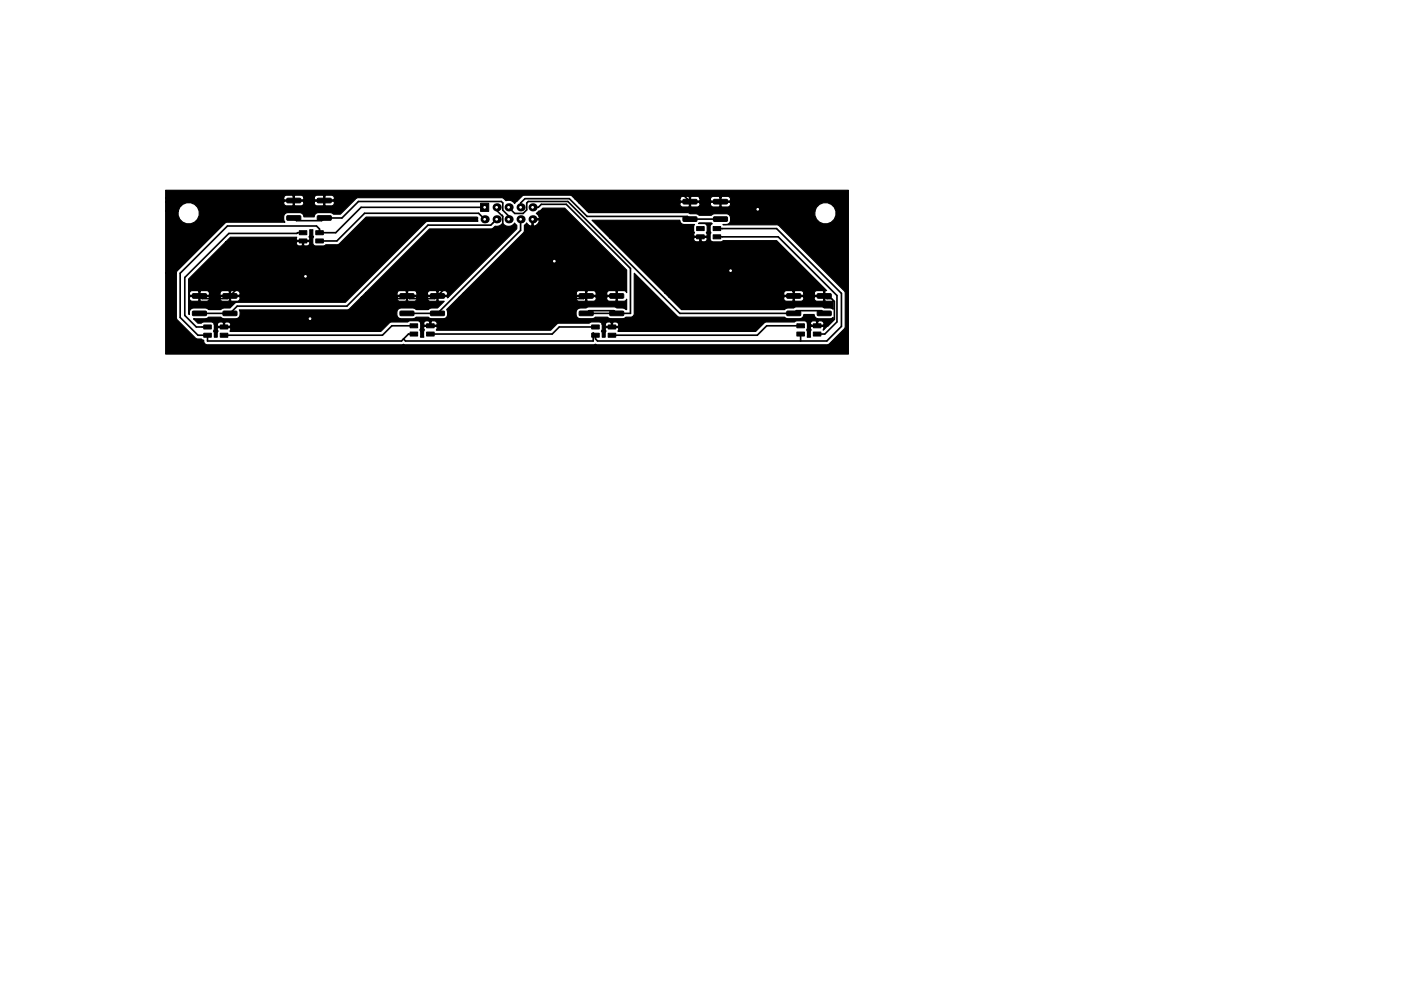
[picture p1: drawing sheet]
<svg xmlns="http://www.w3.org/2000/svg" width="297mm" height="210mm" viewBox="0 0 297 210" stroke-linecap="round" stroke-linejoin="round" font-family="sans-serif">
<g fill="#000" stroke="#000" stroke-width=".21">
<path d="M63.4 50.7h1.6v.8h-1.6zM63.4 48.9h1.6v.9h-1.6zM60.9 42.1h2.7l.2 .1v.7l-.2 .1h-2.6l-.2-.2zM60.9 45.8h2.7l.2 .1v.7l-.2 .1h-2.6l-.2-.2zM67 50.7h1.6v.8h-1.6zM67 48.9h1.6v.9h-1.6zM67.3 42.1h2.8l.2 .1v.6l-.3 .2h-2.6l-.1-.2zM67.3 45.8h2.8l.2 .1v.6l-.3 .2h-2.5l-.2-.2zM101.9 43.1h1.7v1.8h-1.7zM144.9 46.1l2.7-.1 .2 .2v.6l-.2 .2h-2.6l-.2-.2zM144.9 42.4l2.7-.1 .2 .2v.6l-.2 .2h-2.6l-.2-.2zM147.7 48.1h1.6v.8h-1.6z"/>
<path d="M147.7 49.8h1.6v.9h-1.6zM151.2 48.1h1.6v.8h-1.6zM151.2 49.8h1.6v.9h-1.6zM151.3 46.1l2.8-.1 .2 .2-.1 .6-.2 .2h-2.5l-.2-.2zM151.3 42.4l2.8-.1 .2 .2-.1 .6-.2 .2h-2.5l-.2-.2zM40.9 62.4l2.7-.1 .2 .2v.6l-.2 .2h-2.6l-.2-.2zM40.9 66.1l2.7-.1 .2 .2v.6l-.2 .2h-2.6l-.2-.2zM43.2 70.7h1.6v.8h-1.6zM43.2 68.9h1.6v.9h-1.6zM46.7 70.7h1.6v.8h-1.6zM46.7 68.9h1.6v.9h-1.6zM47.3 62.4l2.8-.1 .2 .2-.1 .6-.2 .2h-2.6l-.1-.2z"/>
<path d="M47.3 66.1l2.8-.1 .2 .2-.1 .6-.2 .2h-2.6l-.1-.2zM84.9 62.4l2.7-.1 .2 .2v.6l-.2 .2h-2.6l-.2-.2zM84.9 66.1l2.7-.1 .2 .2v.6l-.2 .2h-2.6l-.2-.2zM87 68.7h1.5v.8h-1.5zM87 70.4h1.5v.9h-1.5zM90.4 68.7h1.7v.8h-1.7zM90.4 70.4h1.7v.9h-1.7zM91.3 62.4l2.8-.1 .2 .2v.6l-.3 .2h-2.6l-.1-.2zM91.3 66.1l2.8-.1 .2 .2v.6l-.3 .2h-2.6l-.1-.2zM122.9 66.1l2.7-.1 .2 .2v.6l-.2 .2h-2.6l-.2-.2zM122.9 62.4l2.7-.1 .2 .2v.6l-.2 .2h-2.6l-.2-.2zM125.5 70.7h1.6v.8h-1.6z"/>
<path d="M125.5 68.9h1.6v.9h-1.6zM128.9 70.7h1.6v.8h-1.6zM128.9 68.9h1.6v.9h-1.6zM129.3 66.1l2.8-.1 .2 .2-.1 .6-.2 .2h-2.6l-.1-.2zM129.3 62.4l2.8-.1 .2 .2-.1 .6-.2 .2h-2.6l-.1-.2zM166.9 66.1l2.7-.1 .2 .2v.6l-.2 .2h-2.6l-.2-.2zM166.9 62.4l2.7-.1 .2 .2v.6l-.2 .2h-2.6l-.2-.2zM168.9 68.7h1.7v.8h-1.7zM168.9 70.4h1.7v.9h-1.7zM172.5 68.7h1.5v.8h-1.5zM172.5 70.4h1.5v.9h-1.5zM173.3 66.1l2.8-.1 .2 .2-.1 .6-.2 .2h-2.6l-.1-.2z"/>
<path d="M173.3 62.4l2.8-.1 .2 .2-.1 .6-.2 .2h-2.6l-.1-.2z"/>
<circle cx="64.8" cy="58.6" r=".6"/>
<circle cx="117.5" cy="55.4" r=".6"/>
<circle cx="154.9" cy="57.4" r=".6"/>
<circle cx="160.7" cy="44.4" r=".6"/>
<circle cx="65.7" cy="67.6" r=".6"/>
</g>
<g fill="#000">
<circle cx="102.8" cy="46.5" r=".86"/>
<circle cx="105.3" cy="44" r=".86"/>
<circle cx="105.3" cy="46.5" r=".86"/>
<circle cx="107.8" cy="44" r=".86"/>
<circle cx="107.8" cy="46.5" r=".86"/>
<circle cx="110.4" cy="46.5" r=".86"/>
<circle cx="110.4" cy="44" r=".86"/>
<circle cx="112.9" cy="46.5" r=".86"/>
<circle cx="112.9" cy="44" r=".86"/>
</g>
<g fill="none" stroke="#000" stroke-width=".35">
<path d="M62.3 46.2l.6 .6h5.3l.6-.6h3.7l3.5-3.5h30.3l.3 .3v1.6l1.3 1.3-.1 .6M62.3 42.5h8.4l1.2-1.1h73l1.4 1.4h12.7l1.7 1.6M64.3 51.1h-3.9l-12.2 12.3h-5.3l-.6-.6M64.3 49.4h-1.2l-.2 .1h-14.4l-9.3 9.4v8l2.4 2.5h2.4M64.8 58.6l-4.2 4.2h-11.8M102.8 46.5l-1.3-1.3h-24.2l-5.9 5.9h-3.7M102.8 44h-26.2l-5.4 5.4h-3.5v-.8l-.6-.7h-18.9l-10 10.1v9.3l3.8 3.8h2v1.2h41.1l1.5-1.4h1.1M105.3 44v.6l1.3 1.3v3l-14.4 14.5h-5.3l-.6-.6-.6 .6h-3.5l-1.7 1.6v2.9M105.3 46.5l-1.2 1.3h-13.4l-17.1 17.1h-23.3l-1.5 1.6h-6.5M107.8 44l1.3 1.3h1.8l.8-.8v-1.4l.3-.4h8.4l23.7 23.8h24.2l.6-.6h5.3l.6 .6M110.4 46.5v2.4l-17.6 17.6h-6.5M110.4 44v-.9l.9-1h9.4l3.8 3.8h21.2l.6 .6h6.5"/>
<path d="M112.9 44h1.2l.7-.7h5.3l13.6 13.7v9.5h-9.4l.6-.6h5.3l.6 .6M112.9 46.5v10.9l6 6M117.5 55.4l-4.6 .1M148.5 50.2v.8l11.8 11.8h14.5l.5 .6h1l.6 .5v3.8l-1.4 1.4h-3.4l-1.4-1.4h-52.4l-.4-.3-.3 .3h-26.7l-.1 .2M152 50.2h13l12.4 12.5v5.6l-2.5 2.6h-1.6M152 48.5h12.6l13.8 13.7v7l-3.1 3.1h-48.6l-.5-.4v-.8l-.4-.5v1.7h-39.8l-.5-.4M65.7 67.6h2.3l.3 .3M87.7 69.1h-4.6l-2 2h-33.6M90.8 67.9h-40.7l-1.5 1.5h-1.1M90.8 67.9l.5 .4v.8M118.9 63.4l-1 .9v3.2M126.2 69.4h-7.6l-1.5 1.5h-25.8"/>
<path d="M129.6 67.7l.2 1.7M130.8 62.8h-6.5l-.6 .6h-4.8M169.7 69.1h-7.1l-2 2h-30.8M169.7 70.9v1.4"/>
</g>
<path d="M48.9 50.3h14l-.1 .5 .2 .2h2.5a.48 .48 0 0 0 0-.7 1.81 1.81 0 0 0 .2-1.5h.6a1.81 1.81 0 0 0 .2 1.4 1.73 1.73 0 0 0 0 1.8l.5 .2h1.6l.5-.3h2.6l5.9-5.8h23.5l.2 .1v.8h-10.9l-17.2 17.1h-22.9l-.6 .3-.9 .9h-1.3l-.7 .4h-2.6l-.7-.4h-2.5a1.06 1.06 0 0 0-.9 1.4l-.1-.1v-3.5h.2a.68 .68 0 0 0 .5 .8h1.3l.2-.1v-.9h.2v.9l.2 .1h1.3a.68 .68 0 0 0 .5-.8h2.2a.68 .68 0 0 0 .5 .8h1.4l.1-.1v-.9h.3v.9l.1 .1h1.4a.61 .61 0 0 0 .3-1h-3.9l-.2 .2-6.3-.2-.3 .2v-.9h.2l.1 .5h1.9v-.9h.2v.9h1.9l.1-.5h2.2l.2 .5h1.8v-.9h.3v.9h1.8a.6 .6 0 0 0-.3-1h-1.4l-.1 .1-.4-.1h-1.4l-.5 .5h-2.2l-.5-.5h-1.3l-.2 .1-.4-.1h-1.3l-.7 .5v-3l7.8-7.8h15a.65 .65 0 0 0 .5 .8h.7l.1-.2v-.7h.3v.7l.1 .2h.7a.57 .57 0 0 0 .3-.9h-2.5l-.2 .1h-15zM105.2 43.8l.2 .1v.2h-.3zM106.5 45.6l.1 .1zM41 67.6h2.5l.7-.3h2.6l.7 .3h2.5a1.16 1.16 0 0 0 .7-1.8h22.9l.5-.3 2.5-2.4h7.5a.68 .68 0 0 0 .6 .8h1.3l.2-.1v-.9h.2v.9l.2 .1 1.5-.1 .3-.4v-.3h2.2a.68 .68 0 0 0 .5 .8h1.4l.1-.1v-.9h-1.8l-.2 .2h-2.2l-.1-.2-11.7 .2 .9-.9h6.6l.2 .5h1.9v-.9h.2v.9h1.9l.1-.5h2.2l.2 .5h1.8v-.9h.3v.9h1.8l.2-.2a.68 .68 0 0 0-.5-.8h-1.4l-.1 .1-.4-.1h-1.4l-.5 .5h-2.2l-.5-.5h-1.3l-.2 .1-.4-.1h-1.3l-.6 .5h-6.6l13.6-13.6h13l.3-.1 .6-.5h.1a1.37 1.37 0 0 0 1.5-.7 1.49 1.49 0 0 0 2.5 0l.5 .5v.7l-14.7 14.7-.2-.3h-1.8v.9l.1 .1h1.2l-1.4 1.4h-1.3l-.7 .4h-2.6l-.7-.4h-2.5a1.17 1.17 0 0 0-.9 1.2 1.17 1.17 0 0 0 .9 1.1h2.5l.7-.3h2.6l.7 .3h2.8a1.35 1.35 0 0 0 .4-1.9l2.6-2.6h24.9a.68 .68 0 0 0 .5 .8h1.3l.2-.1v-.9h.2v.9l.2 .1 1.5-.1 .3-.4v-.3h2.2a.68 .68 0 0 0 .5 .8h1.4l.1-.1v-.9h-1.8l-.2 .2h-2.2l-.1-.2h-4l-.1 .2h-24.9l.9-.9h24l.1 .5h1.9v-.9h.2v.9h1.9l.1-.5h2.2l.2 .5h1.8v-.9l-.1-.1h-1.4l-.5 .5h-2.2l-.5-.5h-1.3l-.2 .1-.4-.1h-1.3l-.5 .5h-24l12.8-12.7 .2-.6v-1.1l.5-.5 .4 .5 .5 .2 .2-.1v-1.2h.2v1.2a1.09 1.09 0 0 0 1.4-1l-.1-.2h-1.5v-.3h1.5l.1-.2-.3-.6-.4-.3 1.4-1.1h4.6l13.2 13.1v4.8l-.5-.4h-1.4l-.1 .1v2l.1 .1h1.4l.5-.4v2.2l-.6-.3-1.5-.1-.6-.2h-5.3l-.6 .2h-1.3a1.17 1.17 0 0 0-.9 1.2 1.17 1.17 0 0 0 .9 1.1h2.5l.7-.3h2.6l.7 .3h2.5l.7-.3h1.3a.79 .79 0 0 0 .5-.9v-8.4l9.3 9.3h22.6l.6 .3h2.5a.9 .9 0 0 0 .9-.9h2.2a.9 .9 0 0 0 .9 .9h2.5l.6-.2v.6l-2.1 2a.48 .48 0 0 0 0-.7h-2.5l-.2 .4 .2 .3a1.84 1.84 0 0 0-.1 1.5h-.8l.1-1.1-.2-.4 .2-.5v-.9h.6l.2 .4h1.1v-.8h.3v.8h1.1l.2-.2a.65 .65 0 0 0-.5-.7h-.7l-.1 .1-1.1-.1-.5 .5h-.6l-.2-.4-.4-.1h-1.7l-.5 .2h-5.8l-.6 .2-1.8 1.8h-29.1l.1-.6-.2-.2h-2.5a.48 .48 0 0 0 0 .7l-.2 .5v.8h-.6v-.8a.64 .64 0 0 1 0-.9v-1h.6l.2 .4h1.1v-.7h.3v.7h1.1a.55 .55 0 0 0 .2-.5 .55 .55 0 0 0-.5-.4h-.7l-.1 .2-1.1-.2-.5 .5h-.6l-.2-.3-.4-.2h-1.6l-.6 .3-6.3-.1-.6 .3-1.3 1.3h-24.1l.1-.7-.2-.1h-2.5a.48 .48 0 0 0 0 .7l-.2 .4 .1 1.1h-.8a1.84 1.84 0 0 0-.1-1.5l.2-.5v-.9h.6l.2 .4h1.1v-.8h.3v.8h1.1a.55 .55 0 0 0 .2-.6 .55 .55 0 0 0-.5-.3h-.7l-.1 .1-1.1-.1-.5 .5h-.6l-.2-.4-.5-.1h-1.5l-.6 .2h-3.3l-.6 .2-1.8 1.8h-31.9l.1-.6-.1-.2h-2.6a.48 .48 0 0 0 0 .7l-.1 .5v.8h-.7v-.8a.64 .64 0 0 1 0-.9v-1h.7l.1 .4h1.2v-.7h.2v.7h1.2a.55 .55 0 0 0 .1-.5 .55 .55 0 0 0-.5-.4h-.6l-.2 .2-1-.2-.5 .5h-.7l-.1-.3-.5-.2h-1.6l-.5 .3h-.7zM125.5 46.7h18.6a.9 .9 0 0 0 .9 .9h2.2a1.74 1.74 0 0 0 0 1.8 .48 .48 0 0 0 0 .7h2.6a.48 .48 0 0 0 0-.7 1.73 1.73 0 0 0 0-1.8l-.5-.2h-1.2l.1-.1h2.6l.2 .2-.3 .1a1.73 1.73 0 0 0 0 1.8 1.73 1.73 0 0 0 0 1.7l.5 .2h1.6l.5-.2h11.4l10.6 10.6-.4 .1v2l.1 .1 1.6-.1v1.8l-.3-.2-1.5-.1-.6-.2h-5.3l-.6 .2-1.6 .1-.3 .3h-21.9l-2.6-2.6h24.3a.68 .68 0 0 0 .5 .8h1.3l.2-.1v-.9h.2v.9l.2 .1h1.3a.68 .68 0 0 0 .5-.8h2.2a.68 .68 0 0 0 .5 .8h1.4l.1-.1v-.9h-1.8l-.2 .2h-2.2l-.1-.2h-4l-.1 .2h-24.3l-.9-.9h25.2l.1 .5h1.9v-.9h.2v.9h1.9l.1-.5h2.2l.2 .5h1.8v-.9l-.1-.1h-1.4l-.5 .5h-2.2l-.5-.5h-1.3l-.2 .1-.4-.1h-1.3l-.5 .5h-25.2l-11.7-11.7h17.8a.65 .65 0 0 0 .5 .8h.6l.2-.2v-.7h.2v.7l.2 .2h.6a.57 .57 0 0 0 .4-.9h-2.6l-.1 .1h-17.8zM35.1 40.4h144.8v34.7h-144.8v-17.1h2.3v9.7l4 4 .6 .2h.7l.5 .3a.81 .81 0 0 0 .9 1h41l.4-.2 .5 .2h39.8l.4-.2 .5 .2h48.6l.6-.3 3.3-3.3v-7.4l-.2-.5-14-14-11.7-.1h.7a1.17 1.17 0 0 0 .9-1.1 1.17 1.17 0 0 0-.9-1.2h-2.5l-.7 .4h-2.6l-.3-.3-1.6-.1-.6-.2h-20.9l-.3-.3h48.3a2.28 2.28 0 0 0 2.6 2.7 2.28 2.28 0 0 0 1.5-3.5 2.28 2.28 0 0 0-3.8 0l-.3 .8h-48.3l-1.7-1.7h21.4a.68 .68 0 0 0 .5 .8h1.3l.2-.1v-.9h.2v.9l.2 .1h1.3a.68 .68 0 0 0 .5-.8h2.2a.68 .68 0 0 0 .5 .8h1.4l.1-.1v-.9h.3v.9l.1 .1h1.4a.61 .61 0 0 0 .3-1h-3.9l-.2 .2h-2.2l-.1-.2h-4l-.1 .2h-21.4l-.9-.9h22.3l.1 .5h1.9v-.9h.2v.9h1.9l.1-.5h2.2l.2 .5h1.8v-.9h.3v.9h1.8a.6 .6 0 0 0-.3-1h-1.4l-.1 .1-.4-.1h-1.4l-.5 .5h-2.2l-.5-.5h-1.3l-.2 .1-.4-.1h-1.3l-.5 .5h-22.3l-.6-.6-.6-.3h-9.4l-.6 .3-1.6 1.6a1.46 1.46 0 0 0-1.8-.6l-.4-.4-.6-.3h-30.3l-.6 .3-3.2 3.2h-1.5l-.7-.3h-2.5a.9 .9 0 0 0-.9 .9h-2.2a.9 .9 0 0 0-.9-.9h-2.5a1.25 1.25 0 0 0-.6 2l-12.5 .1-10.3 10.2-.2 .6h-2.3v-13.2h2.7a2.28 2.28 0 0 0 2.6 2.7 2.28 2.28 0 0 0 1.5-3.5 2.28 2.28 0 0 0-3.8 0l-.3 .8h-2.7v-2h25a.68 .68 0 0 0 .6 .9h1.3l.2-.2v-.8h.2v.8l.2 .2h1.3a.68 .68 0 0 0 .5-.9h2.2a.68 .68 0 0 0 .5 .9h1.4l.1-.2v-.8h.3v.8l.1 .2h1.4a.61 .61 0 0 0 .3-1h-3.9l-.2 .1h-2.2l-.1-.1h-4l-.2 .1h-25v-.9h25l.2 .5h1.9v-.8h.2v.8h1.9l.1-.5h2.2l.2 .5h1.8v-.8h.3v.8h1.8a.6 .6 0 0 0-.3-1h-1.4l-.1 .2-.4-.2h-1.4l-.5 .5h-2.2l-.5-.5h-1.3l-.2 .2-.4-.2h-1.3l-.6 .5h-25z" fill="#000" stroke="#000" stroke-width=".25"/>
<g fill="#fff" stroke="#fff" stroke-width=".21">
<circle cx="117.5" cy="55.4" r=".17"/>
<circle cx="154.9" cy="57.4" r=".17"/>
<circle cx="160.7" cy="44.4" r=".17"/>
<circle cx="64.8" cy="58.6" r=".17"/>
<circle cx="65.7" cy="67.6" r=".17"/>
<circle cx="112.9" cy="46.5" r=".17"/>
<circle cx="112.9" cy="44" r=".17"/>
<circle cx="110.4" cy="46.5" r=".17"/>
<circle cx="110.4" cy="44" r=".17"/>
<circle cx="107.8" cy="46.5" r=".17"/>
<circle cx="107.8" cy="44" r=".17"/>
<circle cx="105.3" cy="46.5" r=".17"/>
<circle cx="105.3" cy="44" r=".17"/>
<circle cx="102.8" cy="46.5" r=".17"/>
<circle cx="102.8" cy="44" r=".17"/>
<circle cx="175" cy="45.2" r=".18"/>
<circle cx="40" cy="45.2" r=".18"/>
</g>
</svg>
